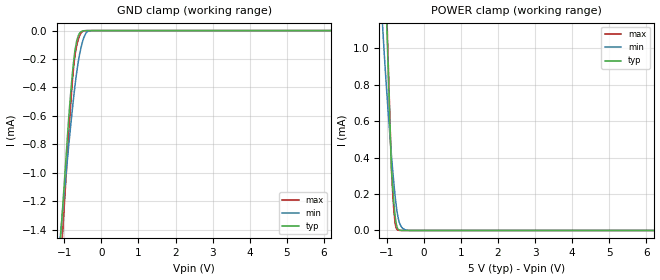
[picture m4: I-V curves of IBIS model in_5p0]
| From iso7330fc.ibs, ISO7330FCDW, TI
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|   in_5p0 Model
[Model]   in_5p0
Model_type   Input
Vinl = 0.8
Vinh = 2
|   typ   min   max
|   (nom PVT)   (slow PVT)   (fast PVT)
C_comp   0.354pF   0.325pF   0.383pF
| Where   nom PVT is  Nominal Process, 5.0V, 27C
|   Fast PVT is Strong Process, 5.5V, -40C
|   Slow PVT is Weak Process, 4.5V, 150C
[Voltage Range]   5   4.5   5.5
[Temperature Range]   27   150   -40
[Power Clamp Reference]   5   4.5   5.5
[GND Clamp Reference]   0   0   0
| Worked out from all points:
|   GND clamp passes 1 mA (typ) near -0.98 V on its own axis
|   POWER clamp passes 1 mA (typ) near -0.98 V on its own axis
[GND Clamp]
|   Voltage   I(typ)   I(min)   I(max)
-5V       -17.38mA   -13.33mA   -21.61mA
-1.1V     -1.454mA   -1.425mA   -1.655mA
-1.055V   -1.281mA   -1.295mA   -1.464mA
-965mV    -935.5uA   -1.04mA    -1.082mA
-881.3mV  -613.7uA   -809.8uA   -726.1uA
-785mV    -311.3uA   -558.5uA   -366.8uA
-740mV    -198uA     -450.5uA   -235.4uA
-665mV    -70.79uA   -290.8uA   -106.8uA
-515mV    -3.659uA   -84.59uA   -8.775uA
-410mV    -199.6nA   -16.03uA   -652.8nA
-245mV    0A         -228.5nA   -2.001nA
10V       0A         0A         0A
[POWER Clamp]
|   Voltage   I(typ)   I(min)   I(max)
-5V       33.7mA     25.25mA    41.12mA
-1.115V   1.853mA    1.128mA    2.014mA
-1.1V     1.758mA    1.074mA    1.867mA
-1.01V    1.185mA    784.1uA    1.253mA
-950mV    802.4uA    611.6uA    843.2uA
-881.3mV  364.7uA    428.8uA    374.3uA
-845mV    249.9uA    339uA      218.5uA
-770mV    70.52uA    178uA      34.14uA
-695mV    7.268uA    70.12uA    1.309uA
-605mV    265.7nA    19.3uA     71.75nA
-365mV    0A         99.63nA    0A
10V       0A         0A         0A
